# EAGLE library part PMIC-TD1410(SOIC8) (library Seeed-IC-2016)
310030105

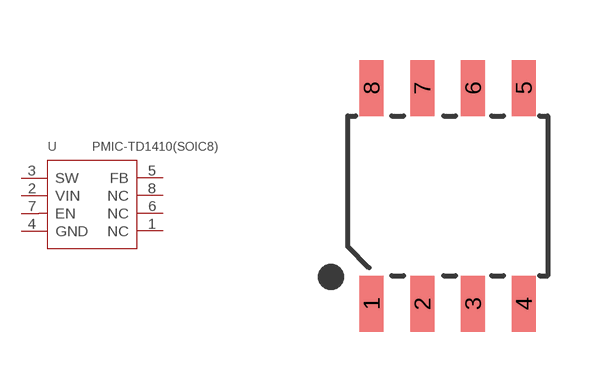
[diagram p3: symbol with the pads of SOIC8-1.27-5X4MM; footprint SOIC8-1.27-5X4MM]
Designator prefix U

## PMIC-TD1410(SOIC8) (MPN: TD1410; VALUE: TD1410-SOIC8)  [SOIC8-1.27-5X4MM]
1  NC  nc
2  VIN  in
3  SW  out
4  GND  sup
5  FB  in
6  NC  nc
7  EN  in
8  NC  nc

## Footprint SOIC8-1.27-5X4MM (pad centres in mm)
smd 0.6 x 1.4: 1 -1.905,-2.7; 2 -0.635,-2.7; 3 0.635,-2.7; 4 1.905,-2.7; 5 1.905,2.7; 6 0.635,2.7; 7 -0.635,2.7; 8 -1.905,2.7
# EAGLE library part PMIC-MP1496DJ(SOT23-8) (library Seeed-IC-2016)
310030121

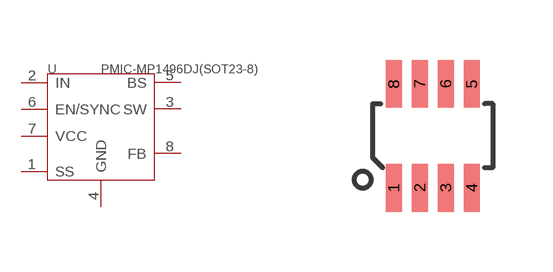
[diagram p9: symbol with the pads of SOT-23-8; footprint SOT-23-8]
Designator prefix U

## PMIC-MP1496DJ(SOT23-8) (MPN: MP1496DJ; VALUE: MP1496DJ-SOT23-8)  [SOT-23-8]
1  SS
2  IN
3  SW
4  GND
5  BS
6  EN/SYNC
7  VCC
8  FB

## Footprint SOT-23-8 (pad centres in mm)
smd 0.4 x 1.2: 1 -0.975,-1.3; 2 -0.325,-1.3; 3 0.325,-1.3; 4 0.975,-1.3; 5 0.975,1.3; 6 0.325,1.3; 7 -0.325,1.3; 8 -0.975,1.3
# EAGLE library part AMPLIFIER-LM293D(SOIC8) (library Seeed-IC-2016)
310020016

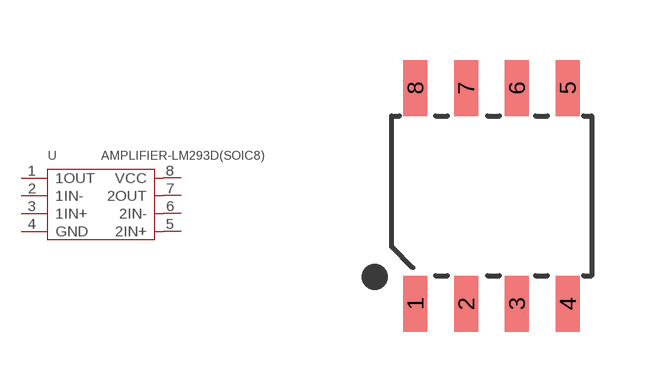
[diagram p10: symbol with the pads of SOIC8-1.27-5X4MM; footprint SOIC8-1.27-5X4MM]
Designator prefix U

## AMPLIFIER-LM293D(SOIC8) (MPN: LM293D; VALUE: LM293D-SOIC8)  [SOIC8-1.27-5X4MM]
1  1OUT  out
2  1IN-  in
3  1IN+  in
4  GND  sup
5  2IN+  in
6  2IN-  in
7  2OUT  out
8  VCC  sup

## Footprint SOIC8-1.27-5X4MM (pad centres in mm)
smd 0.6 x 1.4: 1 -1.905,-2.7; 2 -0.635,-2.7; 3 0.635,-2.7; 4 1.905,-2.7; 5 1.905,2.7; 6 0.635,2.7; 7 -0.635,2.7; 8 -1.905,2.7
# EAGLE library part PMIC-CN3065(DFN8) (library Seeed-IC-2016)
310030101

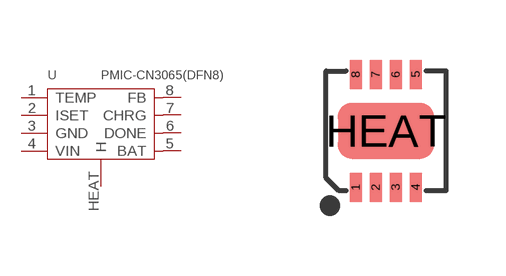
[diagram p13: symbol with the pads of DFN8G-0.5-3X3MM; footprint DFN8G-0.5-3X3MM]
Designator prefix U

## PMIC-CN3065(DFN8) (MPN: CN3065; VALUE: CN3065-DFN8)  [DFN8G-0.5-3X3MM]
1  TEMP  in
2  ISET
3  GND  sup
4  VIN  in
5  BAT
6  DONE
7  CHRG
8  FB  in
HEAT  H

## Footprint DFN8G-0.5-3X3MM (pad centres in mm)
smd 0.3 x 0.727: 1 -0.75,-1.413; 2 -0.25,-1.413; 3 0.25,-1.413; 4 0.75,-1.413; 5 0.75,1.413; 6 0.25,1.413; 7 -0.25,1.413; 8 -0.75,1.413
smd 2.413 x 1.397: HEAT 0,0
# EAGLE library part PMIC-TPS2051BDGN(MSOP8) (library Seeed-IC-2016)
310030211

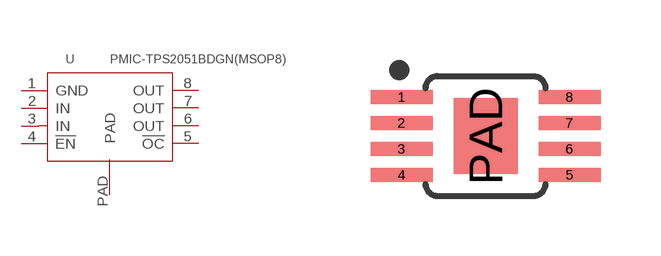
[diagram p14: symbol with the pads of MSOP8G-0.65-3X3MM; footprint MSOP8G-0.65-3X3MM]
Designator prefix U

## PMIC-TPS2051BDGN(MSOP8) (MPN: TPS2051BDGN; VALUE: TPS2051BDGN-MSOP8)  [MSOP8G-0.65-3X3MM]
1  GND  out
2  IN  in
3  IN  in
4  !EN  sup
5  !OC  nc
6  OUT  nc
7  OUT  nc
8  OUT  in
PAD  PAD

## Footprint MSOP8G-0.65-3X3MM (pad centres in mm)
smd 1.55 x 0.35: 1 -2.1,0.975; 2 -2.1,0.325; 3 -2.1,-0.325; 4 -2.1,-0.975; 5 2.1,-0.975; 6 2.1,-0.325; 7 2.1,0.325; 8 2.1,0.975
smd 1.6 x 1.9: PAD 0,0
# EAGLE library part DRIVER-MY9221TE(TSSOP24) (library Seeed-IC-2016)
310040023

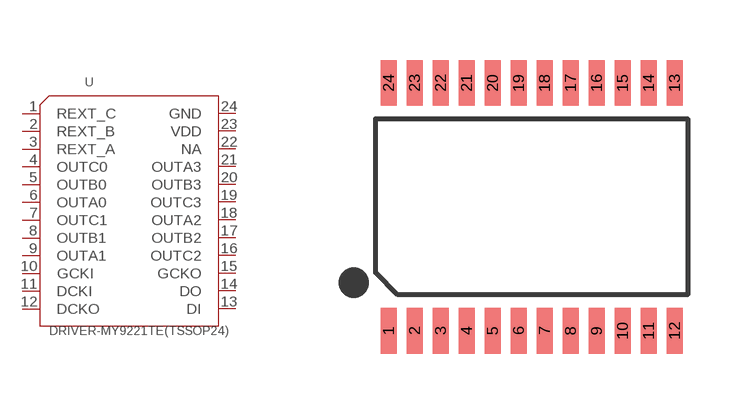
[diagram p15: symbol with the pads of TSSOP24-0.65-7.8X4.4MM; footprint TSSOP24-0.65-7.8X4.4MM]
Designator prefix U

## DRIVER-MY9221TE(TSSOP24) (MPN: MY9221; VALUE: MY9221-tssop24)  [TSSOP24-0.65-7.8X4.4MM]
1  REXT_C
2  REXT_B
3  REXT_A
4  OUTC0
5  OUTB0
6  OUTA0
7  OUTC1
8  OUTB1
9  OUTA1
10  GCKI
11  DCKI
12  DCKO
13  DI
14  DO
15  GCKO
16  OUTC2
17  OUTB2
18  OUTA2
19  OUTC3
20  OUTB3
21  OUTA3
22  NA
23  VDD
24  GND

## Footprint TSSOP24-0.65-7.8X4.4MM (pad centres in mm)
smd 0.4 x 1.15: 1 -3.575,-3.1; 2 -2.925,-3.1; 3 -2.275,-3.1; 4 -1.625,-3.1; 5 -0.975,-3.1; 6 -0.325,-3.1; 7 0.325,-3.1; 8 0.975,-3.1; 9 1.625,-3.1; 10 2.275,-3.1; 11 2.925,-3.1; 12 3.575,-3.1; 13 3.575,3.1; 14 2.925,3.1; 15 2.275,3.1; 16 1.625,3.1; 17 0.975,3.1; 18 0.325,3.1; 19 -0.325,3.1; 20 -0.975,3.1; 21 -1.625,3.1; 22 -2.275,3.1; 23 -2.925,3.1; 24 -3.575,3.1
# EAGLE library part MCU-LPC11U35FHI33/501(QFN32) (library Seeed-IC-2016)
310010053

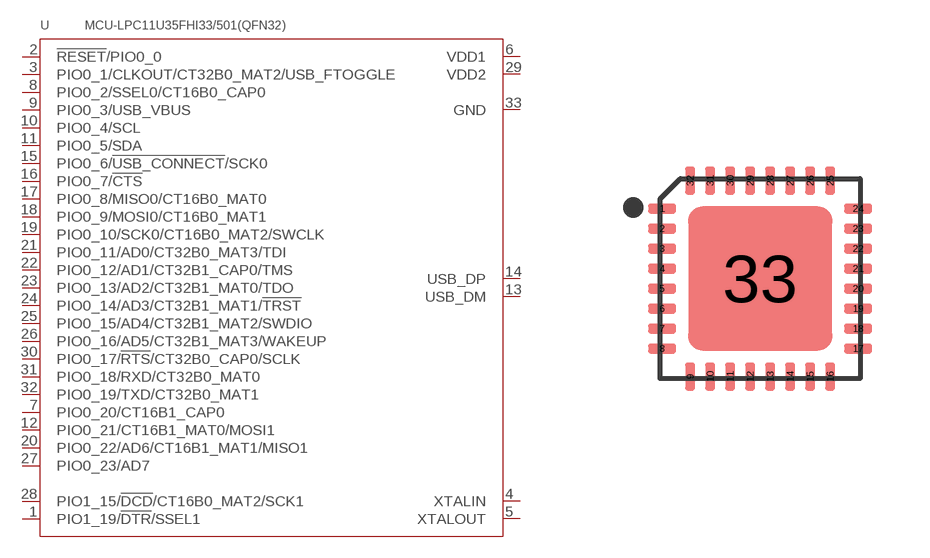
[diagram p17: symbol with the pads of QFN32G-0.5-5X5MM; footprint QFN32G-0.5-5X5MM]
Designator prefix U

## MCU-LPC11U35FHI33/501(QFN32) (MPN: LPC11U35FHI33/501; VALUE: LPC11U35FHI33/501-QFN32)  [QFN32G-0.5-5X5MM]
1  PIO1_19/!DTR!/SSEL1
2  !RESET!/PIO0_0
3  PIO0_1/CLKOUT/CT32B0_MAT2/USB_FTOGGLE
4  XTALIN
5  XTALOUT
6  VDD1
7  PIO0_20/CT16B1_CAP0
8  PIO0_2/SSEL0/CT16B0_CAP0
9  PIO0_3/USB_VBUS
10  PIO0_4/SCL
11  PIO0_5/SDA
12  PIO0_21/CT16B1_MAT0/MOSI1
13  USB_DM
14  USB_DP
15  PIO0_6/!USB_CONNECT!/SCK0
16  PIO0_7/!CTS!
17  PIO0_8/MISO0/CT16B0_MAT0
18  PIO0_9/MOSI0/CT16B0_MAT1
19  PIO0_10/SCK0/CT16B0_MAT2/SWCLK
20  PIO0_22/AD6/CT16B1_MAT1/MISO1
21  PIO0_11/AD0/CT32B0_MAT3/TDI
22  PIO0_12/AD1/CT32B1_CAP0/TMS
23  PIO0_13/AD2/CT32B1_MAT0/TDO
24  PIO0_14/AD3/CT32B1_MAT1/!TRST!
25  PIO0_15/AD4/CT32B1_MAT2/SWDIO
26  PIO0_16/AD5/CT32B1_MAT3/WAKEUP
27  PIO0_23/AD7
28  PIO1_15/!DCD!/CT16B0_MAT2/SCK1
29  VDD2
30  PIO0_17/!RTS!/CT32B0_CAP0/SCLK
31  PIO0_18/RXD/CT32B0_MAT0
32  PIO0_19/TXD/CT32B0_MAT1
33  GND

## Footprint QFN32G-0.5-5X5MM (pad centres in mm)
smd 0.7 x 0.25: 1 -2.45,1.75; 2 -2.45,1.25; 3 -2.45,0.75; 4 -2.45,0.25; 5 -2.45,-0.25; 6 -2.45,-0.75; 7 -2.45,-1.25; 8 -2.45,-1.75; 17 2.45,-1.75; 18 2.45,-1.25; 19 2.45,-0.75; 20 2.45,-0.25; 21 2.45,0.25; 22 2.45,0.75; 23 2.45,1.25; 24 2.45,1.75
smd 0.25 x 0.7: 9 -1.75,-2.45; 10 -1.25,-2.45; 11 -0.75,-2.45; 12 -0.25,-2.45; 13 0.25,-2.45; 14 0.75,-2.45; 15 1.25,-2.45; 16 1.75,-2.45; 25 1.75,2.45; 26 1.25,2.45; 27 0.75,2.45; 28 0.25,2.45; 29 -0.25,2.45; 30 -0.75,2.45; 31 -1.25,2.45; 32 -1.75,2.45
smd 3.6 x 3.6: 33 0,0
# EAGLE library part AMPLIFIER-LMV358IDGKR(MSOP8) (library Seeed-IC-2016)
310020007

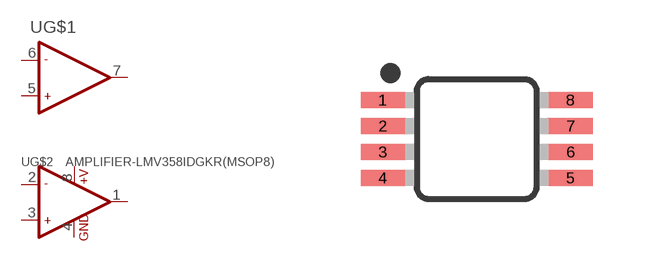
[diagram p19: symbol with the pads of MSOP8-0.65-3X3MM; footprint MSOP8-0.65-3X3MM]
Designator prefix U; gates G$1=OPAMP_2_1 G$2=OPAMP_2

## AMPLIFIER-LMV358IDGKR(MSOP8) (MPN: LMV358IDGKR; VALUE: LMV358IDGKR-MSOP8)  [MSOP8-0.65-3X3MM]
1  G$2:OUT1  out
2  G$2:-IN1  in
3  G$2:+IN1  in
4  G$2:GND  pwr
5  G$1:+IN2  in
6  G$1:-IN2  in
7  G$1:OUT2  out
8  G$2:+V  pwr

## Footprint MSOP8-0.65-3X3MM (pad centres in mm)
8M, 8-Lead, 0.118" Wide, Miniature Small Outline Package MSOP 8M-Package doc1097.pdf
smd 1.1 x 0.4: 1 -2.35,0.975; 2 -2.35,0.325; 3 -2.35,-0.325; 4 -2.35,-0.975; 5 2.35,-0.975; 6 2.35,-0.325; 7 2.35,0.325; 8 2.35,0.975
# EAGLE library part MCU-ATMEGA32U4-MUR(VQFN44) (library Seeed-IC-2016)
310010016

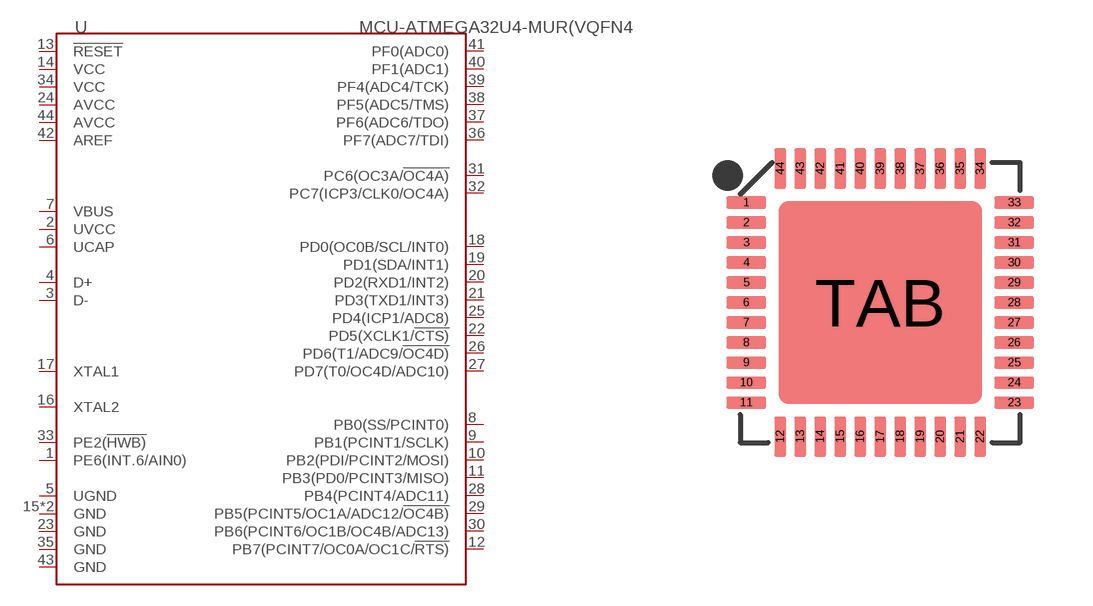
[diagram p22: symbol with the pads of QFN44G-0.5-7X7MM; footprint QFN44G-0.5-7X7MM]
Designator prefix U

## MCU-ATMEGA32U4-MUR(VQFN44) (MPN: ATMEGA32U4-MUR; VALUE: ATMEGA32U4-MUR-QFN44)  [QFN44G-0.5-7X7MM]
1  PE6(INT.6/AIN0)
2  UVCC
3  D-
4  D+
5  UGND
6  UCAP
7  VBUS
8  PB0(SS/PCINT0)
9  PB1(PCINT1/SCLK)
10  PB2(PDI/PCINT2/MOSI)
11  PB3(PD0/PCINT3/MISO)
12  PB7(PCINT7/OC0A/OC1C/!RTS)
13  !RESET
14  VCC
15  GND
16  XTAL2
17  XTAL1
18  PD0(OC0B/SCL/INT0)
19  PD1(SDA/INT1)
20  PD2(RXD1/INT2)
21  PD3(TXD1/INT3)
22  PD5(XCLK1/!CTS)
23  GND
24  AVCC
25  PD4(ICP1/ADC8)
26  PD6(T1/ADC9/!OC4D)
27  PD7(T0/OC4D/ADC10)
28  PB4(PCINT4/ADC11)
29  PB5(PCINT5/OC1A/ADC12/!OC4B)
30  PB6(PCINT6/OC1B/OC4B/ADC13)
31  PC6(OC3A/!OC4A)
32  PC7(ICP3/CLK0/OC4A)
33  PE2(!HWB)
34  VCC
35  GND
36  PF7(ADC7/TDI)
37  PF6(ADC6/TDO)
38  PF5(ADC5/TMS)
39  PF4(ADC4/TCK)
40  PF1(ADC1)
41  PF0(ADC0)
42  AREF
43  GND
44  AVCC
TAB  GND

## Footprint QFN44G-0.5-7X7MM (pad centres in mm)
smd 1 x 0.3: 1 -3.35,2.5; 2 -3.35,2; 3 -3.35,1.5; 4 -3.35,1; 5 -3.35,0.5; 6 -3.35,0; 7 -3.35,-0.5; 8 -3.35,-1; 9 -3.35,-1.5; 10 -3.35,-2; 11 -3.35,-2.5; 23 3.35,-2.5; 24 3.35,-2; 25 3.35,-1.5; 26 3.35,-1; 27 3.35,-0.5; 28 3.35,0; 29 3.35,0.5; 30 3.35,1; 31 3.35,1.5; 32 3.35,2; 33 3.35,2.5
smd 0.3 x 1: 12 -2.5,-3.35; 13 -2,-3.35; 14 -1.5,-3.35; 15 -1,-3.35; 16 -0.5,-3.35; 17 0,-3.35; 18 0.5,-3.35; 19 1,-3.35; 20 1.5,-3.35; 21 2,-3.35; 22 2.5,-3.35; 34 2.5,3.35; 35 2,3.35; 36 1.5,3.35; 37 1,3.35; 38 0.5,3.35; 39 0,3.35; 40 -0.5,3.35; 41 -1,3.35; 42 -1.5,3.35; 43 -2,3.35; 44 -2.5,3.35
smd 5.08 x 5.08: TAB 0,0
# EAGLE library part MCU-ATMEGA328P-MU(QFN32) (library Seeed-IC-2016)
310010005

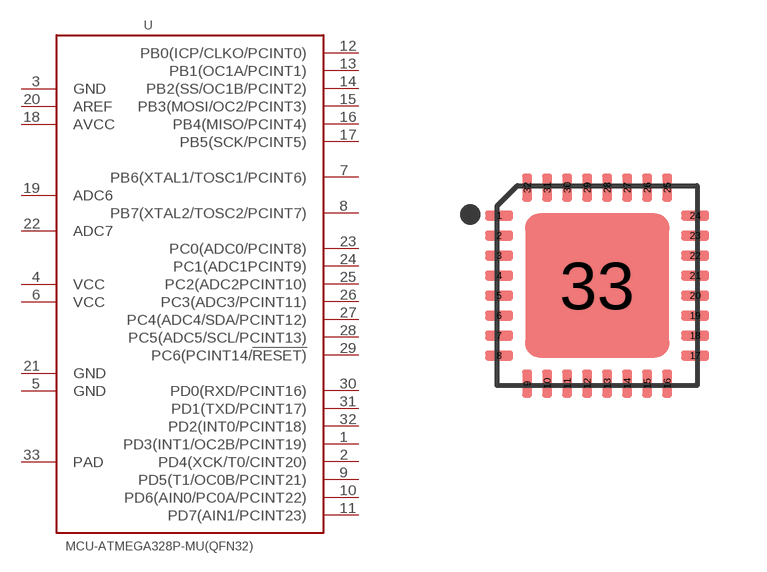
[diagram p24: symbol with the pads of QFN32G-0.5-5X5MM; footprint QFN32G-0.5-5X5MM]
Designator prefix U

## MCU-ATMEGA328P-MU(QFN32) (MPN: ATMEGA328P-MU; VALUE: ATMEGA328P-MU-QFN32)  [QFN32G-0.5-5X5MM]
1  PD3(INT1/OC2B/PCINT19)
2  PD4(XCK/T0/CINT20)
3  GND
4  VCC
5  GND
6  VCC
7  PB6(XTAL1/TOSC1/PCINT6)
8  PB7(XTAL2/TOSC2/PCINT7)
9  PD5(T1/OC0B/PCINT21)
10  PD6(AIN0/PC0A/PCINT22)
11  PD7(AIN1/PCINT23)
12  PB0(ICP/CLKO/PCINT0)
13  PB1(OC1A/PCINT1)
14  PB2(SS/OC1B/PCINT2)
15  PB3(MOSI/OC2/PCINT3)
16  PB4(MISO/PCINT4)
17  PB5(SCK/PCINT5)
18  AVCC
19  ADC6
20  AREF
21  GND
22  ADC7
23  PC0(ADC0/PCINT8)
24  PC1(ADC1PCINT9)
25  PC2(ADC2PCINT10)
26  PC3(ADC3/PCINT11)
27  PC4(ADC4/SDA/PCINT12)
28  PC5(ADC5/SCL/PCINT13)
29  PC6(PCINT14/!RESET)
30  PD0(RXD/PCINT16)
31  PD1(TXD/PCINT17)
32  PD2(INT0/PCINT18)
33  PAD

## Footprint QFN32G-0.5-5X5MM (pad centres in mm)
smd 0.7 x 0.25: 1 -2.45,1.75; 2 -2.45,1.25; 3 -2.45,0.75; 4 -2.45,0.25; 5 -2.45,-0.25; 6 -2.45,-0.75; 7 -2.45,-1.25; 8 -2.45,-1.75; 17 2.45,-1.75; 18 2.45,-1.25; 19 2.45,-0.75; 20 2.45,-0.25; 21 2.45,0.25; 22 2.45,0.75; 23 2.45,1.25; 24 2.45,1.75
smd 0.25 x 0.7: 9 -1.75,-2.45; 10 -1.25,-2.45; 11 -0.75,-2.45; 12 -0.25,-2.45; 13 0.25,-2.45; 14 0.75,-2.45; 15 1.25,-2.45; 16 1.75,-2.45; 25 1.75,2.45; 26 1.25,2.45; 27 0.75,2.45; 28 0.25,2.45; 29 -0.25,2.45; 30 -0.75,2.45; 31 -1.25,2.45; 32 -1.75,2.45
smd 3.6 x 3.6: 33 0,0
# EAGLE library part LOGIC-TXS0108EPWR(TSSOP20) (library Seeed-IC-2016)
310050026

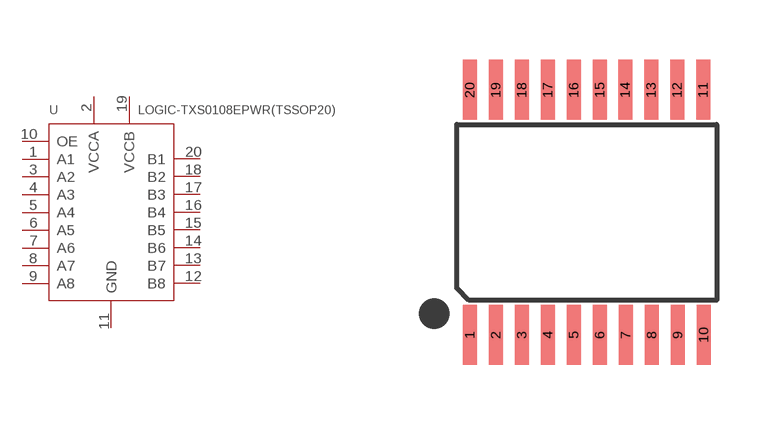
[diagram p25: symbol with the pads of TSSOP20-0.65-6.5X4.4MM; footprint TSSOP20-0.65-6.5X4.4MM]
Designator prefix U

## LOGIC-TXS0108EPWR(TSSOP20) (MPN: TXS0108EPWR; VALUE: TXS0108EPWR-TSSOP20)  [TSSOP20-0.65-6.5X4.4MM]
1  A1
2  VCCA
3  A2
4  A3
5  A4
6  A5
7  A6
8  A7
9  A8
10  OE
11  GND
12  B8
13  B7
14  B6
15  B5
16  B4
17  B3
18  B2
19  VCCB
20  B1

## Footprint TSSOP20-0.65-6.5X4.4MM (pad centres in mm)
smd 0.35 x 1.5: 1 -2.925,-3.065; 2 -2.275,-3.065; 3 -1.625,-3.065; 4 -0.975,-3.065; 5 -0.325,-3.065; 6 0.325,-3.065; 7 0.975,-3.065; 8 1.625,-3.065; 9 2.275,-3.065; 10 2.925,-3.065; 11 2.91,3.065; 12 2.26,3.065; 13 1.61,3.065; 14 0.96,3.065; 15 0.325,3.065; 16 -0.325,3.065; 17 -0.975,3.065; 18 -1.625,3.065; 19 -2.275,3.065; 20 -2.925,3.065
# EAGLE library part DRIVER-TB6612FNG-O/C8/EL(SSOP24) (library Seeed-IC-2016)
310040007

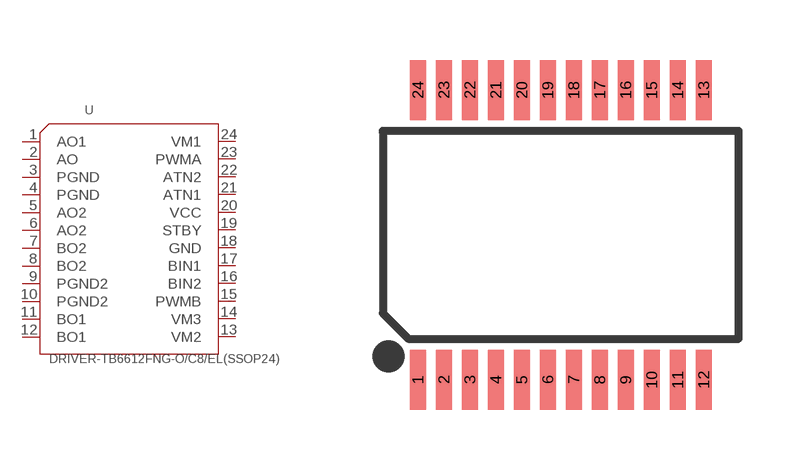
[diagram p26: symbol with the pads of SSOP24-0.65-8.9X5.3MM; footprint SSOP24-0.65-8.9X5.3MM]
Designator prefix -

## DRIVER-TB6612FNG-O/C8/EL(SSOP24) (MPN: TB6612FNG-O/C8/EL; VALUE: TB6612FNG-O/C8/EL-SSOP24)  [SSOP24-0.65-8.9X5.3MM]
1  AO1
2  AO
3  PGND
4  PGND
5  AO2
6  AO2
7  BO2
8  BO2
9  PGND2
10  PGND2
11  BO1
12  BO1
13  VM2
14  VM3
15  PWMB
16  BIN2
17  BIN1
18  GND
19  STBY
20  VCC
21  ATN1
22  ATN2
23  PWMA
24  VM1

## Footprint SSOP24-0.65-8.9X5.3MM (pad centres in mm)
smd 0.4 x 1.5: 1 -3.575,-3.625; 2 -2.925,-3.625; 3 -2.275,-3.625; 4 -1.625,-3.625; 5 -0.975,-3.625; 6 -0.325,-3.625; 7 0.325,-3.625; 8 0.975,-3.625; 9 1.625,-3.625; 10 2.275,-3.625; 11 2.925,-3.625; 12 3.575,-3.625; 13 3.575,3.625; 14 2.925,3.625; 15 2.275,3.625; 16 1.625,3.625; 17 0.975,3.625; 18 0.325,3.625; 19 -0.325,3.625; 20 -0.975,3.625; 21 -1.625,3.625; 22 -2.275,3.625; 23 -2.925,3.625; 24 -3.575,3.625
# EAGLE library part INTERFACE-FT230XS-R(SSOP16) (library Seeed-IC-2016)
310070030

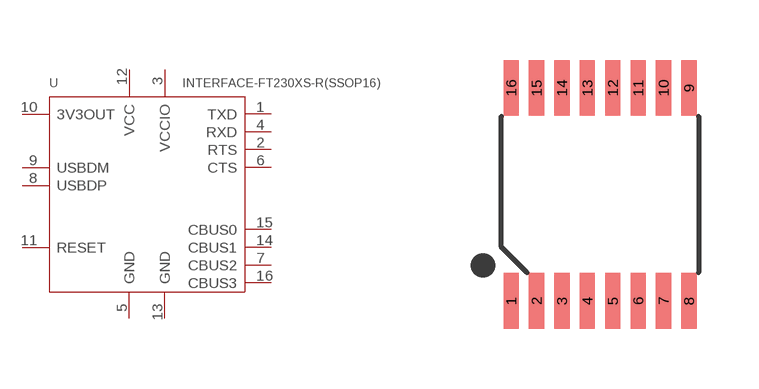
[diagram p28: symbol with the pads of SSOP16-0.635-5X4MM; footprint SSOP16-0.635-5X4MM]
Designator prefix U

## INTERFACE-FT230XS-R(SSOP16) (MPN: FT230XS-R; VALUE: FT230XS-R-SSOP16)  [SSOP16-0.635-5X4MM]
1  TXD
2  RTS
3  VCCIO
4  RXD
5  GND
6  CTS
7  CBUS2
8  USBDP
9  USBDM
10  3V3OUT
11  RESET
12  VCC
13  GND
14  CBUS1
15  CBUS0
16  CBUS3

## Footprint SSOP16-0.635-5X4MM (pad centres in mm)
smd 0.381 x 1.397: 1 -2.223,-2.667; 2 -1.587,-2.667; 3 -0.953,-2.667; 4 -0.318,-2.667; 5 0.318,-2.667; 6 0.953,-2.667; 7 1.587,-2.667; 8 2.223,-2.667; 9 2.223,2.667; 10 1.587,2.667; 11 0.953,2.667; 12 0.318,2.667; 13 -0.318,2.667; 14 -0.953,2.667; 15 -1.587,2.667; 16 -2.223,2.667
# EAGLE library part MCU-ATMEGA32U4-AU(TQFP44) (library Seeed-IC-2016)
310010010

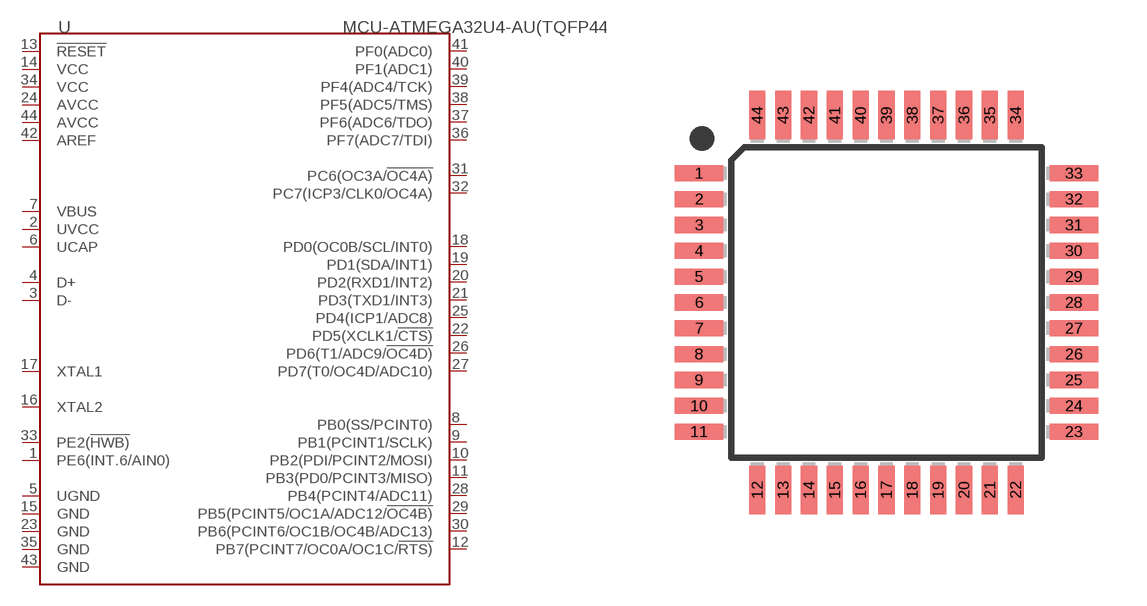
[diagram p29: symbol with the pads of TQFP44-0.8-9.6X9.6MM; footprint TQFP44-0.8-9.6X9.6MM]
Designator prefix U

## MCU-ATMEGA32U4-AU(TQFP44) (MPN: ATMEGA32U4; VALUE: ATMEGA32U4-TQFP44)  [TQFP44-0.8-9.6X9.6MM]
1  PE6(INT.6/AIN0)
2  UVCC
3  D-
4  D+
5  UGND
6  UCAP
7  VBUS
8  PB0(SS/PCINT0)
9  PB1(PCINT1/SCLK)
10  PB2(PDI/PCINT2/MOSI)
11  PB3(PD0/PCINT3/MISO)
12  PB7(PCINT7/OC0A/OC1C/!RTS)
13  !RESET
14  VCC
15  GND
16  XTAL2
17  XTAL1
18  PD0(OC0B/SCL/INT0)
19  PD1(SDA/INT1)
20  PD2(RXD1/INT2)
21  PD3(TXD1/INT3)
22  PD5(XCLK1/!CTS)
23  GND
24  AVCC
25  PD4(ICP1/ADC8)
26  PD6(T1/ADC9/!OC4D)
27  PD7(T0/OC4D/ADC10)
28  PB4(PCINT4/ADC11)
29  PB5(PCINT5/OC1A/ADC12/!OC4B)
30  PB6(PCINT6/OC1B/OC4B/ADC13)
31  PC6(OC3A/!OC4A)
32  PC7(ICP3/CLK0/OC4A)
33  PE2(!HWB)
34  VCC
35  GND
36  PF7(ADC7/TDI)
37  PF6(ADC6/TDO)
38  PF5(ADC5/TMS)
39  PF4(ADC4/TCK)
40  PF1(ADC1)
41  PF0(ADC0)
42  AREF
43  GND
44  AVCC

## Footprint TQFP44-0.8-9.6X9.6MM (pad centres in mm)
Thin Plasic Quad Flat Package
smd 1.5 x 0.5: 1 -5.8,4; 2 -5.8,3.2; 3 -5.8,2.4; 4 -5.8,1.6; 5 -5.8,0.8; 6 -5.8,0; 7 -5.8,-0.8; 8 -5.8,-1.6; 9 -5.8,-2.4; 10 -5.8,-3.2; 11 -5.8,-4; 23 5.8,-4; 24 5.8,-3.2; 25 5.8,-2.4; 26 5.8,-1.6; 27 5.8,-0.8; 28 5.8,0; 29 5.8,0.8; 30 5.8,1.6; 31 5.8,2.4; 32 5.8,3.2; 33 5.8,4
smd 0.5 x 1.5: 12 -4,-5.8; 13 -3.2,-5.8; 14 -2.4,-5.8; 15 -1.6,-5.8; 16 -0.8,-5.8; 17 0,-5.8; 18 0.8,-5.8; 19 1.6,-5.8; 20 2.4,-5.8; 21 3.2,-5.8; 22 4,-5.8; 34 4,5.8; 35 3.2,5.8; 36 2.4,5.8; 37 1.6,5.8; 38 0.8,5.8; 39 0,5.8; 40 -0.8,5.8; 41 -1.6,5.8; 42 -2.4,5.8; 43 -3.2,5.8; 44 -4,5.8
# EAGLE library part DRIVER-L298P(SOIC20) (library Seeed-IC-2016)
310040018

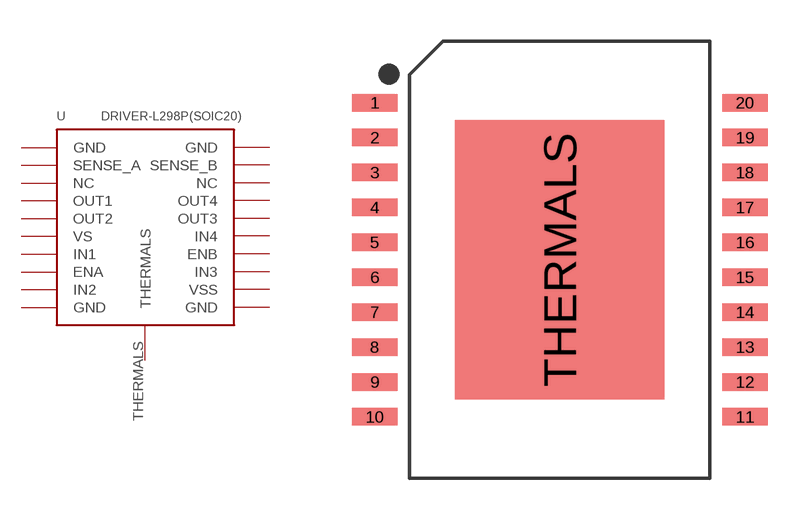
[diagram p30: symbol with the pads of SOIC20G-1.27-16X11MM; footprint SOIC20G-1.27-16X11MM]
Designator prefix U

## DRIVER-L298P(SOIC20) (MPN: L298P; VALUE: L298P-SOIC20)  [SOIC20G-1.27-16X11MM]
1  GND
2  SENSE_A
3  NC
4  OUT1
5  OUT2
6  VS
7  IN1
8  ENA
9  IN2
10  GND
11  GND
12  VSS
13  IN3
14  ENB
15  IN4
16  OUT3
17  OUT4
18  NC
19  SENSE_B
20  GND
THERMALS  THERMALS

## Footprint SOIC20G-1.27-16X11MM (pad centres in mm)
smd 1.651 x 0.635: 1 -6.731,5.715; 2 -6.731,4.445; 3 -6.731,3.175; 4 -6.731,1.905; 5 -6.731,0.635; 6 -6.731,-0.635; 7 -6.731,-1.905; 8 -6.731,-3.175; 9 -6.731,-4.445; 10 -6.731,-5.715; 11 6.731,-5.715; 12 6.731,-4.445; 13 6.731,-3.175; 14 6.731,-1.905; 15 6.731,-0.635; 16 6.731,0.635; 17 6.731,1.905; 18 6.731,3.175; 19 6.731,4.445; 20 6.731,5.715
smd 7.62 x 10.16: THERMALS 0,0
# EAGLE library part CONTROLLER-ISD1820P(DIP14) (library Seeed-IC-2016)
310060021

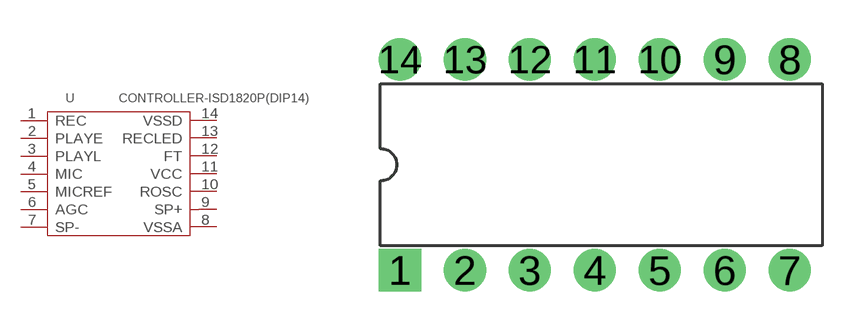
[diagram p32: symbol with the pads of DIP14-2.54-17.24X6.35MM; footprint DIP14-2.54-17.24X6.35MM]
Designator prefix U

## CONTROLLER-ISD1820P(DIP14)  [DIP14-2.54-17.24X6.35MM]
1  REC
2  PLAYE
3  PLAYL
4  MIC
5  MICREF
6  AGC
7  SP-
8  VSSA
9  SP+
10  ROSC
11  VCC
12  FT
13  RECLED
14  VSSD

## Footprint DIP14-2.54-17.24X6.35MM (pad centres in mm)
drill 0.889 pad 1.651 square: 1 -7.62,-4.128
drill 0.889 pad 1.651: 2 -5.08,-4.128; 3 -2.54,-4.128; 4 0,-4.128; 5 2.54,-4.128; 6 5.08,-4.128; 7 7.62,-4.128; 8 7.62,4.128; 9 5.08,4.128; 10 2.54,4.128; 11 0,4.128; 12 -2.54,4.128; 13 -5.08,4.128; 14 -7.62,4.128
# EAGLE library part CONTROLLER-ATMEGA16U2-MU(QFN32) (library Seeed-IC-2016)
310010018

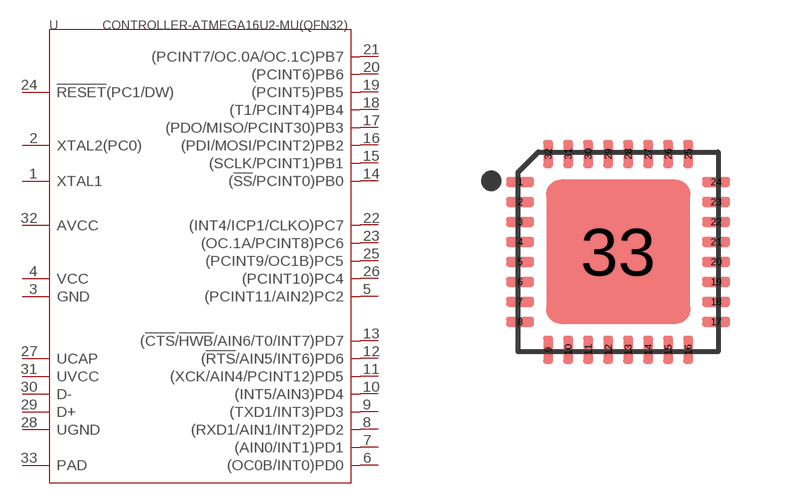
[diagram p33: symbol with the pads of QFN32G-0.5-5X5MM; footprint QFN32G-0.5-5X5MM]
Designator prefix U

## CONTROLLER-ATMEGA16U2-MU(QFN32)  [QFN32G-0.5-5X5MM]
1  XTAL1
2  XTAL2(PC0)
3  GND
4  VCC
5  (PCINT11/AIN2)PC2
6  (OC0B/INT0)PD0
7  (AIN0/INT1)PD1
8  (RXD1/AIN1/INT2)PD2
9  (TXD1/INT3)PD3
10  (INT5/AIN3)PD4
11  (XCK/AIN4/PCINT12)PD5
12  (!RTS!/AIN5/INT6)PD6
13  (!CTS!/!HWB!/AIN6/T0/INT7)PD7
14  (!SS!/PCINT0)PB0
15  (SCLK/PCINT1)PB1
16  (PDI/MOSI/PCINT2)PB2
17  (PDO/MISO/PCINT30)PB3
18  (T1/PCINT4)PB4
19  (PCINT5)PB5
20  (PCINT6)PB6
21  (PCINT7/OC.0A/OC.1C)PB7
22  (INT4/ICP1/CLKO)PC7
23  (OC.1A/PCINT8)PC6
24  !RESET!(PC1/DW)
25  (PCINT9/OC1B)PC5
26  (PCINT10)PC4
27  UCAP
28  UGND
29  D+
30  D-
31  UVCC
32  AVCC
33  PAD

## Footprint QFN32G-0.5-5X5MM (pad centres in mm)
smd 0.7 x 0.25: 1 -2.45,1.75; 2 -2.45,1.25; 3 -2.45,0.75; 4 -2.45,0.25; 5 -2.45,-0.25; 6 -2.45,-0.75; 7 -2.45,-1.25; 8 -2.45,-1.75; 17 2.45,-1.75; 18 2.45,-1.25; 19 2.45,-0.75; 20 2.45,-0.25; 21 2.45,0.25; 22 2.45,0.75; 23 2.45,1.25; 24 2.45,1.75
smd 0.25 x 0.7: 9 -1.75,-2.45; 10 -1.25,-2.45; 11 -0.75,-2.45; 12 -0.25,-2.45; 13 0.25,-2.45; 14 0.75,-2.45; 15 1.25,-2.45; 16 1.75,-2.45; 25 1.75,2.45; 26 1.25,2.45; 27 0.75,2.45; 28 0.25,2.45; 29 -0.25,2.45; 30 -0.75,2.45; 31 -1.25,2.45; 32 -1.75,2.45
smd 3.6 x 3.6: 33 0,0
